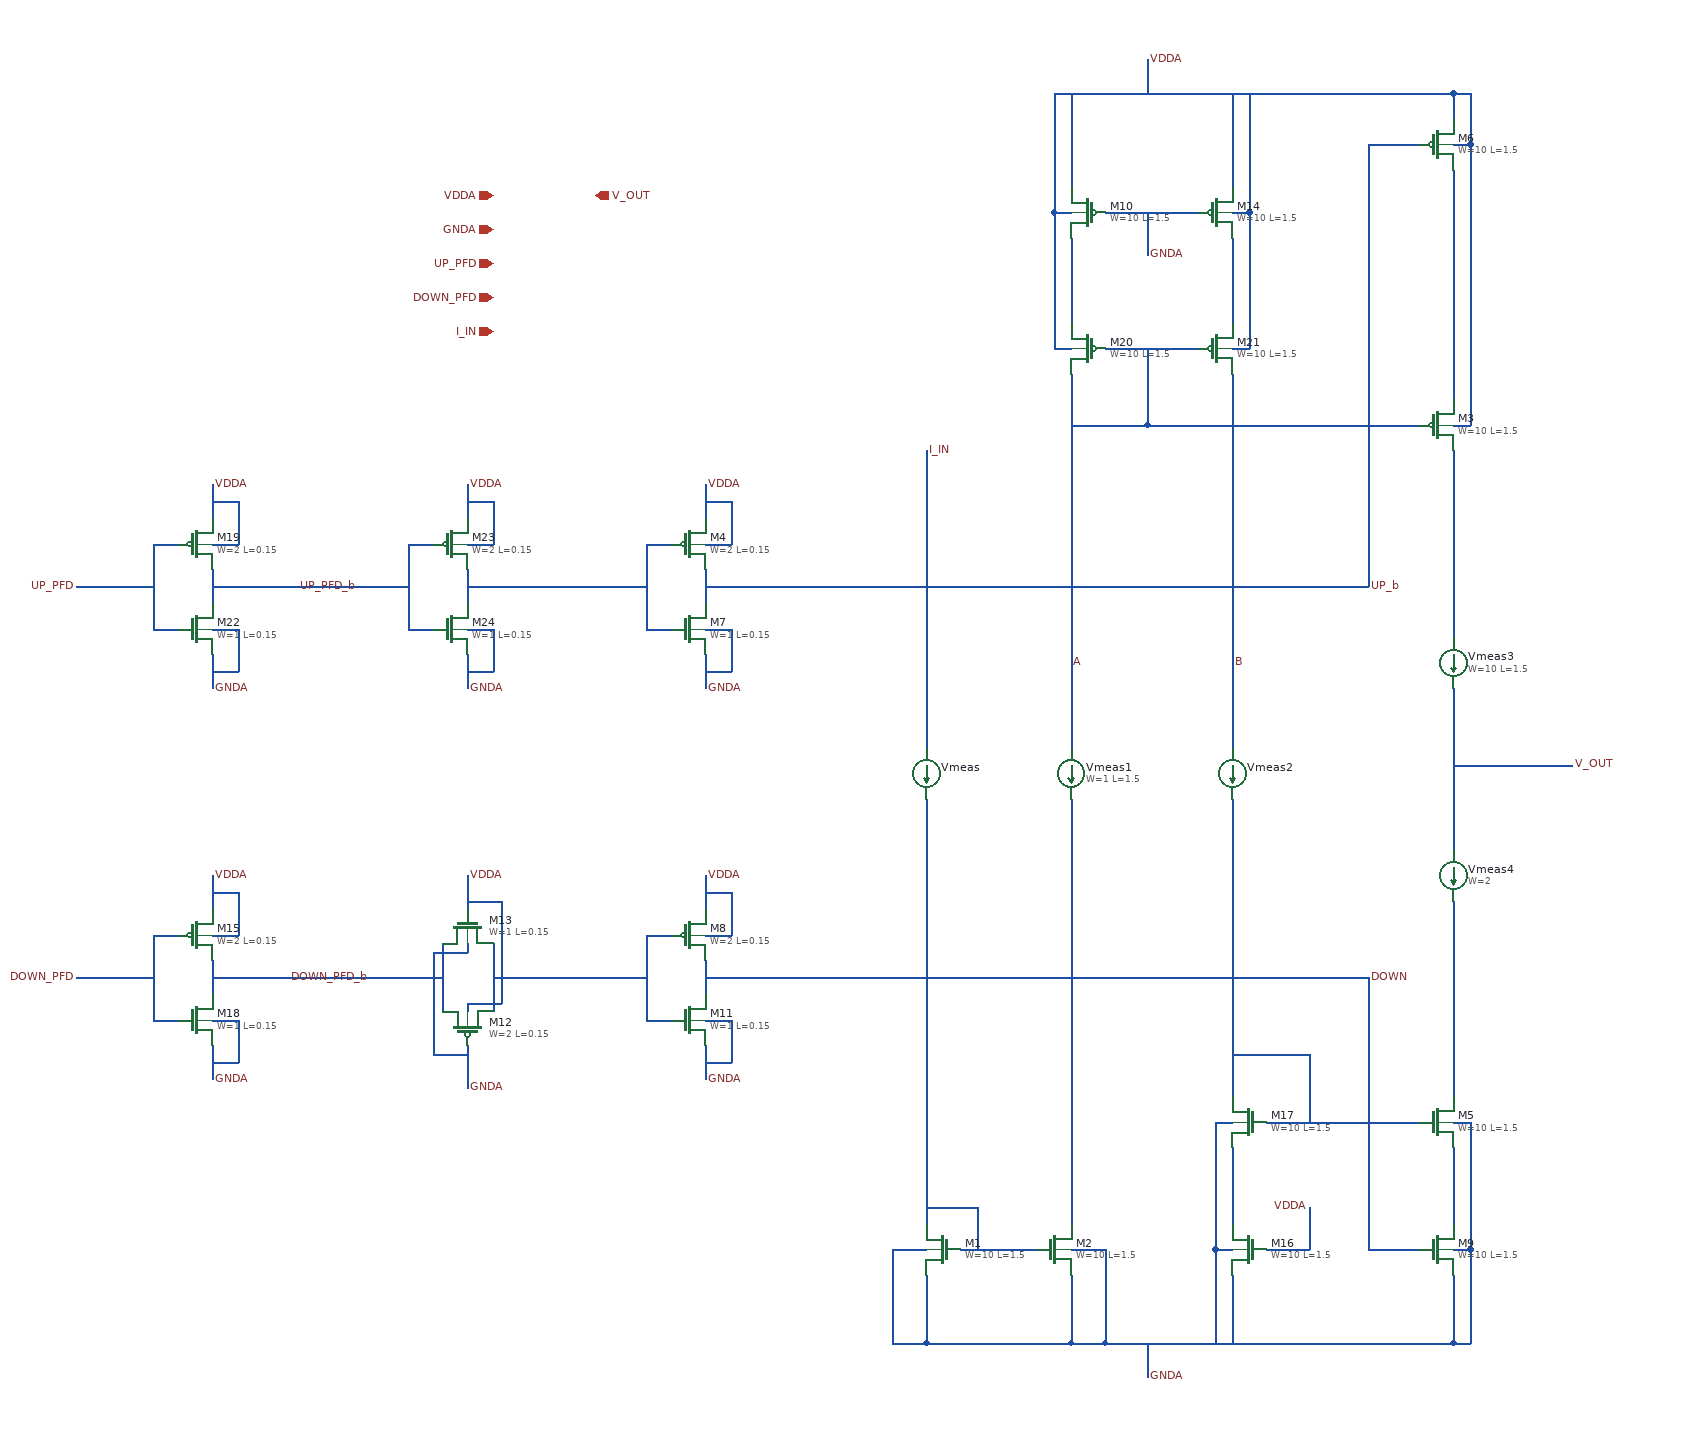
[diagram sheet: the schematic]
v {xschem version=3.4.5 file_version=1.2
}
G {}
K {}
V {}
S {}
E {}
N 380 -950 480 -950 {
lab=UP_PFD_b}
N 380 -490 550 -490 {
lab=UP_PFD_b}
N 120 -950 160 -950 {
lab=UP_PFD}
N 120 -490 160 -490 {
lab=DOWN_PFD}
N 550 -530 550 -450 {
lab=UP_PFD_b}
N 610 -530 610 -450 {
lab=#net1}
N 580 -610 580 -570 {
lab=VDDA}
N 580 -460 580 -450 {
lab=VDDA}
N 580 -460 620 -460 {
lab=VDDA}
N 620 -580 620 -460 {
lab=VDDA}
N 580 -580 620 -580 {
lab=VDDA}
N 580 -530 580 -520 {
lab=GNDA}
N 540 -520 580 -520 {
lab=GNDA}
N 540 -520 540 -400 {
lab=GNDA}
N 540 -400 580 -400 {
lab=GNDA}
N 580 -410 580 -360 {
lab=GNDA}
N 280 -510 280 -470 {
lab=UP_PFD_b}
N 210 -540 240 -540 {
lab=DOWN_PFD}
N 210 -540 210 -440 {
lab=DOWN_PFD}
N 210 -440 240 -440 {
lab=DOWN_PFD}
N 280 -490 380 -490 {
lab=UP_PFD_b}
N 160 -490 210 -490 {
lab=DOWN_PFD}
N 280 -410 280 -370 {
lab=GNDA}
N 280 -610 280 -570 {
lab=VDDA}
N 280 -540 310 -540 {
lab=VDDA}
N 310 -590 310 -540 {
lab=VDDA}
N 280 -590 310 -590 {
lab=VDDA}
N 280 -440 310 -440 {
lab=GNDA}
N 310 -440 310 -390 {
lab=GNDA}
N 280 -390 310 -390 {
lab=GNDA}
N 280 -970 280 -930 {
lab=UP_PFD_b}
N 210 -1000 240 -1000 {
lab=UP_PFD}
N 210 -1000 210 -900 {
lab=UP_PFD}
N 210 -900 240 -900 {
lab=UP_PFD}
N 280 -950 380 -950 {
lab=UP_PFD_b}
N 160 -950 210 -950 {
lab=UP_PFD}
N 280 -870 280 -830 {
lab=GNDA}
N 280 -1070 280 -1030 {
lab=VDDA}
N 280 -1000 310 -1000 {
lab=VDDA}
N 310 -1050 310 -1000 {
lab=VDDA}
N 280 -1050 310 -1050 {
lab=VDDA}
N 280 -900 310 -900 {
lab=GNDA}
N 310 -900 310 -850 {
lab=GNDA}
N 280 -850 310 -850 {
lab=GNDA}
N 580 -970 580 -930 {
lab=#net2}
N 510 -1000 540 -1000 {
lab=UP_PFD_b}
N 510 -1000 510 -900 {
lab=UP_PFD_b}
N 510 -900 540 -900 {
lab=UP_PFD_b}
N 480 -950 510 -950 {
lab=UP_PFD_b}
N 580 -870 580 -830 {
lab=GNDA}
N 580 -1070 580 -1030 {
lab=VDDA}
N 580 -1000 610 -1000 {
lab=VDDA}
N 610 -1050 610 -1000 {
lab=VDDA}
N 580 -1050 610 -1050 {
lab=VDDA}
N 580 -900 610 -900 {
lab=GNDA}
N 610 -900 610 -850 {
lab=GNDA}
N 580 -850 610 -850 {
lab=GNDA}
N 1160 -170 1250 -170 {
lab=#net3}
N 1120 -140 1120 -60 {
lab=GNDA}
N 1120 -60 1290 -60 {
lab=GNDA}
N 1080 -170 1120 -170 {
lab=GNDA}
N 1080 -170 1080 -60 {
lab=GNDA}
N 1080 -60 1120 -60 {
lab=GNDA}
N 1330 -170 1330 -60 {
lab=GNDA}
N 1290 -140 1290 -60 {
lab=GNDA}
N 1180 -220 1180 -170 {
lab=#net3}
N 1290 -60 1330 -60 {
lab=GNDA}
N 1120 -1110 1120 -1060 {
lab=I_IN}
N 1120 -1060 1120 -760 {
lab=I_IN}
N 1740 -1530 1740 -1500 {
lab=VDDA}
N 1560 -1530 1740 -1530 {
lab=VDDA}
N 1740 -1530 1760 -1530 {
lab=VDDA}
N 1760 -1530 1760 -1470 {
lab=VDDA}
N 1740 -1470 1760 -1470 {
lab=VDDA}
N 1330 -60 1640 -60 {
lab=GNDA}
N 1740 -140 1740 -60 {
lab=GNDA}
N 1640 -60 1740 -60 {
lab=GNDA}
N 1740 -170 1760 -170 {
lab=GNDA}
N 1760 -170 1760 -60 {
lab=GNDA}
N 1740 -60 1760 -60 {
lab=GNDA}
N 1740 -460 1740 -350 {
lab=#net4}
N 1740 -290 1740 -200 {
lab=#net5}
N 1740 -1110 1740 -990 {
lab=#net6}
N 1740 -1440 1740 -1230 {
lab=#net7}
N 1740 -1140 1760 -1140 {
lab=VDDA}
N 1740 -320 1760 -320 {
lab=GNDA}
N 1290 -170 1330 -170 {
lab=GNDA}
N 1270 -1390 1290 -1390 {
lab=VDDA}
N 1270 -1530 1270 -1390 {
lab=VDDA}
N 1270 -1530 1560 -1530 {
lab=VDDA}
N 1330 -1390 1440 -1390 {
lab=GNDA}
N 1380 -1390 1380 -1340 {
lab=GNDA}
N 1480 -1390 1500 -1390 {
lab=VDDA}
N 1500 -1530 1500 -1390 {
lab=VDDA}
N 1460 -170 1480 -170 {
lab=GNDA}
N 1480 -290 1480 -200 {
lab=#net8}
N 1460 -320 1480 -320 {
lab=GNDA}
N 1460 -320 1460 -170 {
lab=GNDA}
N 1270 -1230 1290 -1230 {
lab=VDDA}
N 1330 -1230 1440 -1230 {
lab=A}
N 1290 -1360 1290 -1260 {
lab=#net9}
N 1480 -1360 1480 -1260 {
lab=#net10}
N 1380 -1230 1380 -1140 {
lab=A}
N 1480 -1230 1500 -1230 {
lab=VDDA}
N 1500 -1390 1500 -1230 {
lab=VDDA}
N 1270 -1390 1270 -1230 {
lab=VDDA}
N 1570 -400 1570 -320 {
lab=#net11}
N 1480 -400 1570 -400 {
lab=#net11}
N 1740 -580 1740 -520 {
lab=#net4}
N 1740 -750 1740 -640 {
lab=V_OUT}
N 1290 -1200 1290 -760 {
lab=A}
N 1480 -700 1480 -350 {
lab=#net11}
N 1480 -1200 1480 -760 {
lab=B}
N 1480 -1530 1480 -1420 {
lab=VDDA}
N 1290 -1530 1290 -1420 {
lab=VDDA}
N 1480 -140 1480 -60 {
lab=GNDA}
N 1460 -170 1460 -60 {
lab=GNDA}
N 1570 -220 1570 -170 {
lab=VDDA}
N 1740 -830 1740 -750 {
lab=V_OUT}
N 1520 -320 1700 -320 {
lab=#net11}
N 1120 -290 1120 -200 {
lab=#net3}
N 1120 -700 1120 -350 {
lab=#net3}
N 1290 -290 1290 -200 {
lab=#net12}
N 1290 -700 1290 -350 {
lab=#net12}
N 1290 -1140 1380 -1140 {
lab=A}
N 1120 -220 1180 -220 {
lab=#net3}
N 1740 -1230 1740 -1170 {
lab=#net7}
N 1120 -350 1120 -290 {
lab=#net3}
N 1290 -350 1290 -290 {
lab=#net12}
N 1520 -170 1570 -170 {
lab=VDDA}
N 1380 -1140 1700 -1140 {
lab=A}
N 1760 -1470 1760 -1140 {
lab=VDDA}
N 1640 -1470 1640 -950 {
lab=UP_b}
N 1640 -1470 1700 -1470 {
lab=UP_b}
N 1740 -990 1740 -890 {
lab=#net6}
N 1760 -320 1760 -170 {
lab=GNDA}
N 1740 -520 1740 -460 {
lab=#net4}
N 1640 -490 1640 -170 {
lab=DOWN}
N 1640 -170 1700 -170 {
lab=DOWN}
N 1740 -740 1880 -740 {
lab=V_OUT}
N 1380 -1570 1380 -1530 {
lab=VDDA}
N 1380 -60 1380 -20 {
lab=GNDA}
N 860 -970 860 -930 {
lab=UP_b}
N 790 -1000 820 -1000 {
lab=#net2}
N 790 -1000 790 -900 {
lab=#net2}
N 790 -900 820 -900 {
lab=#net2}
N 860 -870 860 -830 {
lab=GNDA}
N 860 -1070 860 -1030 {
lab=VDDA}
N 860 -1000 890 -1000 {
lab=VDDA}
N 890 -1050 890 -1000 {
lab=VDDA}
N 860 -1050 890 -1050 {
lab=VDDA}
N 860 -900 890 -900 {
lab=GNDA}
N 890 -900 890 -850 {
lab=GNDA}
N 860 -850 890 -850 {
lab=GNDA}
N 860 -510 860 -470 {
lab=DOWN}
N 790 -540 820 -540 {
lab=#net1}
N 790 -540 790 -440 {
lab=#net1}
N 790 -440 820 -440 {
lab=#net1}
N 860 -410 860 -370 {
lab=GNDA}
N 860 -610 860 -570 {
lab=VDDA}
N 860 -540 890 -540 {
lab=VDDA}
N 890 -590 890 -540 {
lab=VDDA}
N 860 -590 890 -590 {
lab=VDDA}
N 860 -440 890 -440 {
lab=GNDA}
N 890 -440 890 -390 {
lab=GNDA}
N 860 -390 890 -390 {
lab=GNDA}
N 610 -490 790 -490 {
lab=#net1}
N 580 -950 790 -950 {
lab=#net2}
N 860 -490 1640 -490 {
lab=DOWN}
N 860 -950 1640 -950 {
lab=UP_b}
C {devices/ipin.sym} 610 -1410 0 0 {name=p3 lab=VDDA}
C {devices/opin.sym} 730 -1410 0 0 {name=p11 lab=V_OUT}
C {devices/ipin.sym} 610 -1370 0 0 {name=p35 lab=GNDA}
C {devices/ipin.sym} 610 -1330 0 0 {name=p36 lab=UP_PFD}
C {devices/ipin.sym} 610 -1290 0 0 {name=p37 lab=DOWN_PFD}
C {devices/ipin.sym} 610 -1250 0 0 {name=p38 lab=I_IN}
C {devices/lab_wire.sym} 380 -950 0 1 {name=p15 sig_type=std_logic lab=UP_PFD_b}
C {devices/lab_wire.sym} 120 -950 0 0 {name=p2 sig_type=std_logic lab=UP_PFD}
C {devices/lab_wire.sym} 120 -490 2 1 {name=p7 sig_type=std_logic lab=DOWN_PFD}
C {sky130_fd_pr/pfet_01v8.sym} 580 -430 3 0 {name=M12
L=0.15
W=2
nf=2
mult=1
ad="'int((nf+1)/2) * W/nf * 0.29'" 
pd="'2*int((nf+1)/2) * (W/nf + 0.29)'"
as="'int((nf+2)/2) * W/nf * 0.29'" 
ps="'2*int((nf+2)/2) * (W/nf + 0.29)'"
nrd="'0.29 / W'" nrs="'0.29 / W'"
sa=0 sb=0 sd=0
model=pfet_01v8
spiceprefix=X
}
C {sky130_fd_pr/nfet_01v8.sym} 580 -550 1 0 {name=M13
L=0.15
W=1
nf=1 
mult=1
ad="'int((nf+1)/2) * W/nf * 0.29'" 
pd="'2*int((nf+1)/2) * (W/nf + 0.29)'"
as="'int((nf+2)/2) * W/nf * 0.29'" 
ps="'2*int((nf+2)/2) * (W/nf + 0.29)'"
nrd="'0.29 / W'" nrs="'0.29 / W'"
sa=0 sb=0 sd=0
model=nfet_01v8
spiceprefix=X
}
C {sky130_fd_pr/pfet_01v8.sym} 260 -540 0 0 {name=M15
L=0.15
W=2
nf=2
mult=1
ad="'int((nf+1)/2) * W/nf * 0.29'" 
pd="'2*int((nf+1)/2) * (W/nf + 0.29)'"
as="'int((nf+2)/2) * W/nf * 0.29'" 
ps="'2*int((nf+2)/2) * (W/nf + 0.29)'"
nrd="'0.29 / W'" nrs="'0.29 / W'"
sa=0 sb=0 sd=0
model=pfet_01v8
spiceprefix=X
}
C {sky130_fd_pr/nfet_01v8.sym} 260 -440 2 1 {name=M18
L=0.15
W=1
nf=1 
mult=1
ad="'int((nf+1)/2) * W/nf * 0.29'" 
pd="'2*int((nf+1)/2) * (W/nf + 0.29)'"
as="'int((nf+2)/2) * W/nf * 0.29'" 
ps="'2*int((nf+2)/2) * (W/nf + 0.29)'"
nrd="'0.29 / W'" nrs="'0.29 / W'"
sa=0 sb=0 sd=0
model=nfet_01v8
spiceprefix=X
}
C {sky130_fd_pr/pfet_01v8.sym} 260 -1000 0 0 {name=M19
L=0.15
W=2
nf=2
mult=1
ad="'int((nf+1)/2) * W/nf * 0.29'" 
pd="'2*int((nf+1)/2) * (W/nf + 0.29)'"
as="'int((nf+2)/2) * W/nf * 0.29'" 
ps="'2*int((nf+2)/2) * (W/nf + 0.29)'"
nrd="'0.29 / W'" nrs="'0.29 / W'"
sa=0 sb=0 sd=0
model=pfet_01v8
spiceprefix=X
}
C {sky130_fd_pr/nfet_01v8.sym} 260 -900 2 1 {name=M22
L=0.15
W=1
nf=1 
mult=1
ad="'int((nf+1)/2) * W/nf * 0.29'" 
pd="'2*int((nf+1)/2) * (W/nf + 0.29)'"
as="'int((nf+2)/2) * W/nf * 0.29'" 
ps="'2*int((nf+2)/2) * (W/nf + 0.29)'"
nrd="'0.29 / W'" nrs="'0.29 / W'"
sa=0 sb=0 sd=0
model=nfet_01v8
spiceprefix=X
}
C {sky130_fd_pr/pfet_01v8.sym} 560 -1000 0 0 {name=M23
L=0.15
W=2
nf=2
mult=1
ad="'int((nf+1)/2) * W/nf * 0.29'" 
pd="'2*int((nf+1)/2) * (W/nf + 0.29)'"
as="'int((nf+2)/2) * W/nf * 0.29'" 
ps="'2*int((nf+2)/2) * (W/nf + 0.29)'"
nrd="'0.29 / W'" nrs="'0.29 / W'"
sa=0 sb=0 sd=0
model=pfet_01v8
spiceprefix=X
}
C {sky130_fd_pr/nfet_01v8.sym} 560 -900 2 1 {name=M24
L=0.15
W=1
nf=1 
mult=1
ad="'int((nf+1)/2) * W/nf * 0.29'" 
pd="'2*int((nf+1)/2) * (W/nf + 0.29)'"
as="'int((nf+2)/2) * W/nf * 0.29'" 
ps="'2*int((nf+2)/2) * (W/nf + 0.29)'"
nrd="'0.29 / W'" nrs="'0.29 / W'"
sa=0 sb=0 sd=0
model=nfet_01v8
spiceprefix=X
}
C {devices/lab_pin.sym} 280 -370 0 1 {name=p27 sig_type=std_logic lab=GNDA}
C {devices/lab_pin.sym} 280 -610 0 1 {name=p28 sig_type=std_logic lab=VDDA}
C {devices/lab_pin.sym} 580 -360 0 1 {name=p29 sig_type=std_logic lab=GNDA}
C {devices/lab_pin.sym} 580 -610 0 1 {name=p30 sig_type=std_logic lab=VDDA}
C {devices/lab_pin.sym} 280 -830 0 1 {name=p31 sig_type=std_logic lab=GNDA}
C {devices/lab_pin.sym} 280 -1070 0 1 {name=p32 sig_type=std_logic lab=VDDA}
C {devices/lab_pin.sym} 580 -830 0 1 {name=p33 sig_type=std_logic lab=GNDA}
C {devices/lab_pin.sym} 580 -1070 0 1 {name=p34 sig_type=std_logic lab=VDDA}
C {sky130_fd_pr/nfet_01v8.sym} 1140 -170 0 1 {name=M1
L=1.5
W=10
nf=12 
mult=1
ad="'int((nf+1)/2) * W/nf * 0.29'" 
pd="'2*int((nf+1)/2) * (W/nf + 0.29)'"
as="'int((nf+2)/2) * W/nf * 0.29'" 
ps="'2*int((nf+2)/2) * (W/nf + 0.29)'"
nrd="'0.29 / W'" nrs="'0.29 / W'"
sa=0 sb=0 sd=0
model=nfet_01v8
spiceprefix=X
}
C {sky130_fd_pr/nfet_01v8.sym} 1270 -170 0 0 {name=M2
L=1.5
W=10
nf=12 
mult=1
ad="'int((nf+1)/2) * W/nf * 0.29'" 
pd="'2*int((nf+1)/2) * (W/nf + 0.29)'"
as="'int((nf+2)/2) * W/nf * 0.29'" 
ps="'2*int((nf+2)/2) * (W/nf + 0.29)'"
nrd="'0.29 / W'" nrs="'0.29 / W'"
sa=0 sb=0 sd=0
model=nfet_01v8
spiceprefix=X
}
C {devices/ammeter.sym} 1120 -730 0 0 {name=Vmeas savecurrent=true spice_ignore=0}
C {sky130_fd_pr/pfet_01v8.sym} 1720 -1470 0 0 {name=M6
L=1.5
W=10
nf=1
mult=30
ad="'int((nf+1)/2) * W/nf * 0.29'" 
pd="'2*int((nf+1)/2) * (W/nf + 0.29)'"
as="'int((nf+2)/2) * W/nf * 0.29'" 
ps="'2*int((nf+2)/2) * (W/nf + 0.29)'"
nrd="'0.29 / W'" nrs="'0.29 / W'"
sa=0 sb=0 sd=0
model=pfet_01v8
spiceprefix=X
}
C {devices/ammeter.sym} 1480 -730 0 0 {name=Vmeas2 savecurrent=true spice_ignore=0
nf=2}
C {devices/ammeter.sym} 1740 -860 0 0 {name=Vmeas3 savecurrent=true spice_ignore=0
L=1.5
W=10
nf=1
mult=12}
C {sky130_fd_pr/nfet_01v8.sym} 1720 -170 0 0 {name=M9
L=1.5
W=10
nf=12 
mult=1
ad="'int((nf+1)/2) * W/nf * 0.29'" 
pd="'2*int((nf+1)/2) * (W/nf + 0.29)'"
as="'int((nf+2)/2) * W/nf * 0.29'" 
ps="'2*int((nf+2)/2) * (W/nf + 0.29)'"
nrd="'0.29 / W'" nrs="'0.29 / W'"
sa=0 sb=0 sd=0
model=nfet_01v8
spiceprefix=X
}
C {sky130_fd_pr/pfet_01v8.sym} 1720 -1140 0 0 {name=M3
L=1.5
W=10
nf=1
mult=30
ad="'int((nf+1)/2) * W/nf * 0.29'" 
pd="'2*int((nf+1)/2) * (W/nf + 0.29)'"
as="'int((nf+2)/2) * W/nf * 0.29'" 
ps="'2*int((nf+2)/2) * (W/nf + 0.29)'"
nrd="'0.29 / W'" nrs="'0.29 / W'"
sa=0 sb=0 sd=0
model=pfet_01v8
spiceprefix=X
}
C {sky130_fd_pr/nfet_01v8.sym} 1720 -320 0 0 {name=M5
L=1.5
W=10
nf=12 
mult=1
ad="'int((nf+1)/2) * W/nf * 0.29'" 
pd="'2*int((nf+1)/2) * (W/nf + 0.29)'"
as="'int((nf+2)/2) * W/nf * 0.29'" 
ps="'2*int((nf+2)/2) * (W/nf + 0.29)'"
nrd="'0.29 / W'" nrs="'0.29 / W'"
sa=0 sb=0 sd=0
model=nfet_01v8
spiceprefix=X
}
C {sky130_fd_pr/pfet_01v8.sym} 1310 -1390 0 1 {name=M10
L=1.5
W=10
nf=1
mult=30
ad="'int((nf+1)/2) * W/nf * 0.29'" 
pd="'2*int((nf+1)/2) * (W/nf + 0.29)'"
as="'int((nf+2)/2) * W/nf * 0.29'" 
ps="'2*int((nf+2)/2) * (W/nf + 0.29)'"
nrd="'0.29 / W'" nrs="'0.29 / W'"
sa=0 sb=0 sd=0
model=pfet_01v8
spiceprefix=X
}
C {sky130_fd_pr/pfet_01v8.sym} 1460 -1390 0 0 {name=M14
L=1.5
W=10
nf=1
mult=30
ad="'int((nf+1)/2) * W/nf * 0.29'" 
pd="'2*int((nf+1)/2) * (W/nf + 0.29)'"
as="'int((nf+2)/2) * W/nf * 0.29'" 
ps="'2*int((nf+2)/2) * (W/nf + 0.29)'"
nrd="'0.29 / W'" nrs="'0.29 / W'"
sa=0 sb=0 sd=0
model=pfet_01v8
spiceprefix=X
}
C {sky130_fd_pr/nfet_01v8.sym} 1500 -170 0 1 {name=M16
L=1.5
W=10
nf=12 
mult=1
ad="'int((nf+1)/2) * W/nf * 0.29'" 
pd="'2*int((nf+1)/2) * (W/nf + 0.29)'"
as="'int((nf+2)/2) * W/nf * 0.29'" 
ps="'2*int((nf+2)/2) * (W/nf + 0.29)'"
nrd="'0.29 / W'" nrs="'0.29 / W'"
sa=0 sb=0 sd=0
model=nfet_01v8
spiceprefix=X
}
C {sky130_fd_pr/nfet_01v8.sym} 1500 -320 0 1 {name=M17
L=1.5
W=10
nf=12 
mult=1
ad="'int((nf+1)/2) * W/nf * 0.29'" 
pd="'2*int((nf+1)/2) * (W/nf + 0.29)'"
as="'int((nf+2)/2) * W/nf * 0.29'" 
ps="'2*int((nf+2)/2) * (W/nf + 0.29)'"
nrd="'0.29 / W'" nrs="'0.29 / W'"
sa=0 sb=0 sd=0
model=nfet_01v8
spiceprefix=X
}
C {sky130_fd_pr/pfet_01v8.sym} 1310 -1230 0 1 {name=M20
L=1.5
W=10
nf=1
mult=30
ad="'int((nf+1)/2) * W/nf * 0.29'" 
pd="'2*int((nf+1)/2) * (W/nf + 0.29)'"
as="'int((nf+2)/2) * W/nf * 0.29'" 
ps="'2*int((nf+2)/2) * (W/nf + 0.29)'"
nrd="'0.29 / W'" nrs="'0.29 / W'"
sa=0 sb=0 sd=0
model=pfet_01v8
spiceprefix=X
}
C {sky130_fd_pr/pfet_01v8.sym} 1460 -1230 0 0 {name=M21
L=1.5
W=10
nf=1
mult=30
ad="'int((nf+1)/2) * W/nf * 0.29'" 
pd="'2*int((nf+1)/2) * (W/nf + 0.29)'"
as="'int((nf+2)/2) * W/nf * 0.29'" 
ps="'2*int((nf+2)/2) * (W/nf + 0.29)'"
nrd="'0.29 / W'" nrs="'0.29 / W'"
sa=0 sb=0 sd=0
model=pfet_01v8
spiceprefix=X
}
C {devices/ammeter.sym} 1290 -730 0 0 {name=Vmeas1 savecurrent=true spice_ignore=0
L=1.5
W=1
nf=1}
C {devices/ammeter.sym} 1740 -610 0 0 {name=Vmeas4 savecurrent=true spice_ignore=0
W=2
nf=2}
C {devices/lab_wire.sym} 1640 -950 2 0 {name=p5 sig_type=std_logic lab=UP_b
L=1.5
W=10
nf=1
mult=30}
C {devices/lab_wire.sym} 1640 -490 0 1 {name=p6 sig_type=std_logic lab=DOWN
W=10
nf=1
L=1.5
mult=12}
C {devices/lab_wire.sym} 1120 -1110 0 1 {name=p8 sig_type=std_logic lab=I_IN}
C {devices/lab_wire.sym} 1480 -860 0 1 {name=p9 sig_type=std_logic lab=B}
C {devices/lab_wire.sym} 1290 -860 0 1 {name=p10 sig_type=std_logic lab=A}
C {devices/lab_pin.sym} 1880 -740 0 1 {name=p12 sig_type=std_logic lab=V_OUT}
C {devices/lab_pin.sym} 1380 -1340 0 1 {name=p1 sig_type=std_logic lab=GNDA}
C {devices/lab_pin.sym} 1570 -220 0 0 {name=p4 sig_type=std_logic lab=VDDA}
C {devices/lab_pin.sym} 1380 -1570 0 1 {name=p13 sig_type=std_logic lab=VDDA}
C {devices/lab_pin.sym} 1380 -20 0 1 {name=p14 sig_type=std_logic lab=GNDA}
C {sky130_fd_pr/pfet_01v8.sym} 840 -1000 0 0 {name=M4
L=0.15
W=2
nf=2
mult=1
ad="'int((nf+1)/2) * W/nf * 0.29'" 
pd="'2*int((nf+1)/2) * (W/nf + 0.29)'"
as="'int((nf+2)/2) * W/nf * 0.29'" 
ps="'2*int((nf+2)/2) * (W/nf + 0.29)'"
nrd="'0.29 / W'" nrs="'0.29 / W'"
sa=0 sb=0 sd=0
model=pfet_01v8
spiceprefix=X
}
C {sky130_fd_pr/nfet_01v8.sym} 840 -900 2 1 {name=M7
L=0.15
W=1
nf=1 
mult=1
ad="'int((nf+1)/2) * W/nf * 0.29'" 
pd="'2*int((nf+1)/2) * (W/nf + 0.29)'"
as="'int((nf+2)/2) * W/nf * 0.29'" 
ps="'2*int((nf+2)/2) * (W/nf + 0.29)'"
nrd="'0.29 / W'" nrs="'0.29 / W'"
sa=0 sb=0 sd=0
model=nfet_01v8
spiceprefix=X
}
C {devices/lab_pin.sym} 860 -830 0 1 {name=p16 sig_type=std_logic lab=GNDA}
C {devices/lab_pin.sym} 860 -1070 0 1 {name=p17 sig_type=std_logic lab=VDDA}
C {sky130_fd_pr/pfet_01v8.sym} 840 -540 0 0 {name=M8
L=0.15
W=2
nf=2
mult=1
ad="'int((nf+1)/2) * W/nf * 0.29'" 
pd="'2*int((nf+1)/2) * (W/nf + 0.29)'"
as="'int((nf+2)/2) * W/nf * 0.29'" 
ps="'2*int((nf+2)/2) * (W/nf + 0.29)'"
nrd="'0.29 / W'" nrs="'0.29 / W'"
sa=0 sb=0 sd=0
model=pfet_01v8
spiceprefix=X
}
C {sky130_fd_pr/nfet_01v8.sym} 840 -440 2 1 {name=M11
L=0.15
W=1
nf=1 
mult=1
ad="'int((nf+1)/2) * W/nf * 0.29'" 
pd="'2*int((nf+1)/2) * (W/nf + 0.29)'"
as="'int((nf+2)/2) * W/nf * 0.29'" 
ps="'2*int((nf+2)/2) * (W/nf + 0.29)'"
nrd="'0.29 / W'" nrs="'0.29 / W'"
sa=0 sb=0 sd=0
model=nfet_01v8
spiceprefix=X
}
C {devices/lab_pin.sym} 860 -370 0 1 {name=p18 sig_type=std_logic lab=GNDA}
C {devices/lab_pin.sym} 860 -610 0 1 {name=p19 sig_type=std_logic lab=VDDA}
C {devices/lab_wire.sym} 370 -490 2 0 {name=p20 sig_type=std_logic lab=DOWN_PFD_b}
